VERSION 5.7 ;
  NOWIREEXTENSIONATPIN ON ;
  DIVIDERCHAR "/" ;
  BUSBITCHARS "[]" ;
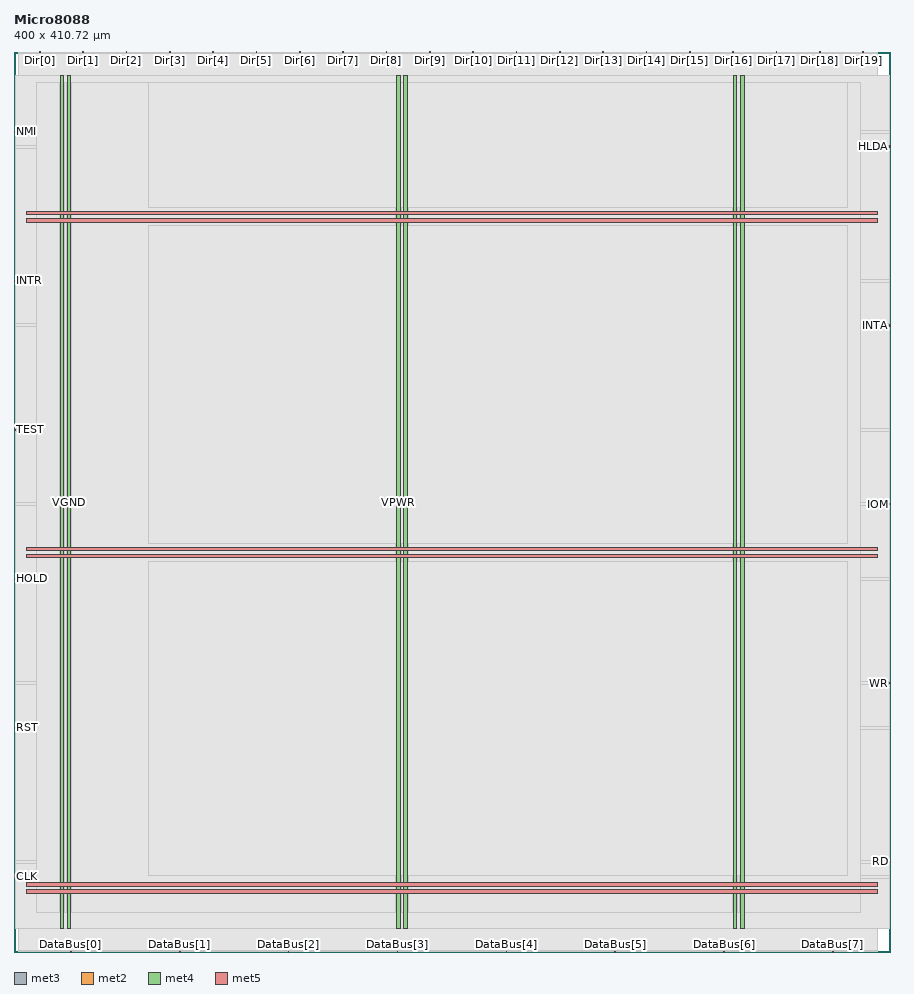
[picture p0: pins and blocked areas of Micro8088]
MACRO Micro8088
  CLASS BLOCK ;
  FOREIGN Micro8088 ;
  ORIGIN 0.000 0.000 ;
  SIZE 400.000 BY 410.720 ;
  PIN CLK
    DIRECTION INPUT ;
    USE SIGNAL ;
    ANTENNAGATEAREA 0.852000 ;
    PORT
      LAYER met3 ;
        RECT 0.000 34.040 0.600 34.640 ;
    END
  END CLK
  PIN DataBus[0]
    DIRECTION INOUT ;
    USE SIGNAL ;
    ANTENNAGATEAREA 0.252000 ;
    ANTENNADIFFAREA 0.445500 ;
    PORT
      LAYER met2 ;
        RECT 25.850 0.000 26.130 0.280 ;
    END
  END DataBus[0]
  PIN DataBus[1]
    DIRECTION INOUT ;
    USE SIGNAL ;
    ANTENNAGATEAREA 0.252000 ;
    ANTENNADIFFAREA 0.445500 ;
    PORT
      LAYER met2 ;
        RECT 75.530 0.000 75.810 0.280 ;
    END
  END DataBus[1]
  PIN DataBus[2]
    DIRECTION INOUT ;
    USE SIGNAL ;
    ANTENNAGATEAREA 0.252000 ;
    ANTENNADIFFAREA 0.445500 ;
    PORT
      LAYER met2 ;
        RECT 125.210 0.000 125.490 0.280 ;
    END
  END DataBus[2]
  PIN DataBus[3]
    DIRECTION INOUT ;
    USE SIGNAL ;
    ANTENNAGATEAREA 0.252000 ;
    ANTENNADIFFAREA 0.445500 ;
    PORT
      LAYER met2 ;
        RECT 174.890 0.000 175.170 0.280 ;
    END
  END DataBus[3]
  PIN DataBus[4]
    DIRECTION INOUT ;
    USE SIGNAL ;
    ANTENNAGATEAREA 0.252000 ;
    ANTENNADIFFAREA 0.445500 ;
    PORT
      LAYER met2 ;
        RECT 224.570 0.000 224.850 0.280 ;
    END
  END DataBus[4]
  PIN DataBus[5]
    DIRECTION INOUT ;
    USE SIGNAL ;
    ANTENNAGATEAREA 0.252000 ;
    ANTENNADIFFAREA 0.445500 ;
    PORT
      LAYER met2 ;
        RECT 274.250 0.000 274.530 0.280 ;
    END
  END DataBus[5]
  PIN DataBus[6]
    DIRECTION INOUT ;
    USE SIGNAL ;
    ANTENNAGATEAREA 0.252000 ;
    ANTENNADIFFAREA 0.445500 ;
    PORT
      LAYER met2 ;
        RECT 323.930 0.000 324.210 0.280 ;
    END
  END DataBus[6]
  PIN DataBus[7]
    DIRECTION INOUT ;
    USE SIGNAL ;
    ANTENNAGATEAREA 0.252000 ;
    ANTENNADIFFAREA 0.445500 ;
    PORT
      LAYER met2 ;
        RECT 373.610 0.000 373.890 0.280 ;
    END
  END DataBus[7]
  PIN Dir[0]
    DIRECTION OUTPUT ;
    USE SIGNAL ;
    ANTENNADIFFAREA 0.702900 ;
    PORT
      LAYER met2 ;
        RECT 11.590 410.440 11.870 410.720 ;
    END
  END Dir[0]
  PIN Dir[10]
    DIRECTION OUTPUT ;
    USE SIGNAL ;
    ANTENNADIFFAREA 0.702900 ;
    PORT
      LAYER met2 ;
        RECT 209.390 410.440 209.670 410.720 ;
    END
  END Dir[10]
  PIN Dir[11]
    DIRECTION OUTPUT ;
    USE SIGNAL ;
    ANTENNADIFFAREA 0.702900 ;
    PORT
      LAYER met2 ;
        RECT 229.170 410.440 229.450 410.720 ;
    END
  END Dir[11]
  PIN Dir[12]
    DIRECTION OUTPUT ;
    USE SIGNAL ;
    ANTENNADIFFAREA 0.702900 ;
    PORT
      LAYER met2 ;
        RECT 248.950 410.440 249.230 410.720 ;
    END
  END Dir[12]
  PIN Dir[13]
    DIRECTION OUTPUT ;
    USE SIGNAL ;
    ANTENNADIFFAREA 0.702900 ;
    PORT
      LAYER met2 ;
        RECT 268.730 410.440 269.010 410.720 ;
    END
  END Dir[13]
  PIN Dir[14]
    DIRECTION OUTPUT ;
    USE SIGNAL ;
    ANTENNADIFFAREA 0.702900 ;
    PORT
      LAYER met2 ;
        RECT 288.510 410.440 288.790 410.720 ;
    END
  END Dir[14]
  PIN Dir[15]
    DIRECTION OUTPUT ;
    USE SIGNAL ;
    ANTENNADIFFAREA 0.702900 ;
    PORT
      LAYER met2 ;
        RECT 308.290 410.440 308.570 410.720 ;
    END
  END Dir[15]
  PIN Dir[16]
    DIRECTION OUTPUT ;
    USE SIGNAL ;
    ANTENNADIFFAREA 0.702900 ;
    PORT
      LAYER met2 ;
        RECT 328.070 410.440 328.350 410.720 ;
    END
  END Dir[16]
  PIN Dir[17]
    DIRECTION OUTPUT ;
    USE SIGNAL ;
    ANTENNADIFFAREA 0.702900 ;
    PORT
      LAYER met2 ;
        RECT 347.850 410.440 348.130 410.720 ;
    END
  END Dir[17]
  PIN Dir[18]
    DIRECTION OUTPUT ;
    USE SIGNAL ;
    ANTENNADIFFAREA 0.702900 ;
    PORT
      LAYER met2 ;
        RECT 367.630 410.440 367.910 410.720 ;
    END
  END Dir[18]
  PIN Dir[19]
    DIRECTION OUTPUT ;
    USE SIGNAL ;
    ANTENNADIFFAREA 0.702900 ;
    PORT
      LAYER met2 ;
        RECT 387.410 410.440 387.690 410.720 ;
    END
  END Dir[19]
  PIN Dir[1]
    DIRECTION OUTPUT ;
    USE SIGNAL ;
    ANTENNADIFFAREA 0.702900 ;
    PORT
      LAYER met2 ;
        RECT 31.370 410.440 31.650 410.720 ;
    END
  END Dir[1]
  PIN Dir[2]
    DIRECTION OUTPUT ;
    USE SIGNAL ;
    ANTENNADIFFAREA 0.702900 ;
    PORT
      LAYER met2 ;
        RECT 51.150 410.440 51.430 410.720 ;
    END
  END Dir[2]
  PIN Dir[3]
    DIRECTION OUTPUT ;
    USE SIGNAL ;
    ANTENNADIFFAREA 0.702900 ;
    PORT
      LAYER met2 ;
        RECT 70.930 410.440 71.210 410.720 ;
    END
  END Dir[3]
  PIN Dir[4]
    DIRECTION OUTPUT ;
    USE SIGNAL ;
    ANTENNADIFFAREA 0.702900 ;
    PORT
      LAYER met2 ;
        RECT 90.710 410.440 90.990 410.720 ;
    END
  END Dir[4]
  PIN Dir[5]
    DIRECTION OUTPUT ;
    USE SIGNAL ;
    ANTENNADIFFAREA 0.702900 ;
    PORT
      LAYER met2 ;
        RECT 110.490 410.440 110.770 410.720 ;
    END
  END Dir[5]
  PIN Dir[6]
    DIRECTION OUTPUT ;
    USE SIGNAL ;
    ANTENNADIFFAREA 0.702900 ;
    PORT
      LAYER met2 ;
        RECT 130.270 410.440 130.550 410.720 ;
    END
  END Dir[6]
  PIN Dir[7]
    DIRECTION OUTPUT ;
    USE SIGNAL ;
    ANTENNADIFFAREA 0.702900 ;
    PORT
      LAYER met2 ;
        RECT 150.050 410.440 150.330 410.720 ;
    END
  END Dir[7]
  PIN Dir[8]
    DIRECTION OUTPUT ;
    USE SIGNAL ;
    ANTENNADIFFAREA 0.702900 ;
    PORT
      LAYER met2 ;
        RECT 169.830 410.440 170.110 410.720 ;
    END
  END Dir[8]
  PIN Dir[9]
    DIRECTION OUTPUT ;
    USE SIGNAL ;
    ANTENNADIFFAREA 0.702900 ;
    PORT
      LAYER met2 ;
        RECT 189.610 410.440 189.890 410.720 ;
    END
  END Dir[9]
  PIN HLDA
    DIRECTION OUTPUT ;
    USE SIGNAL ;
    ANTENNADIFFAREA 0.702900 ;
    PORT
      LAYER met3 ;
        RECT 399.400 367.240 400.000 367.840 ;
    END
  END HLDA
  PIN HOLD
    DIRECTION INPUT ;
    USE SIGNAL ;
    ANTENNAGATEAREA 0.126000 ;
    PORT
      LAYER met3 ;
        RECT 0.000 170.040 0.600 170.640 ;
    END
  END HOLD
  PIN INTA
    DIRECTION OUTPUT ;
    USE SIGNAL ;
    ANTENNADIFFAREA 0.702900 ;
    PORT
      LAYER met3 ;
        RECT 399.400 285.640 400.000 286.240 ;
    END
  END INTA
  PIN INTR
    DIRECTION INPUT ;
    USE SIGNAL ;
    ANTENNAGATEAREA 0.126000 ;
    PORT
      LAYER met3 ;
        RECT 0.000 306.040 0.600 306.640 ;
    END
  END INTR
  PIN IOM
    DIRECTION OUTPUT ;
    USE SIGNAL ;
    ANTENNADIFFAREA 0.702900 ;
    PORT
      LAYER met3 ;
        RECT 399.400 204.040 400.000 204.640 ;
    END
  END IOM
  PIN NMI
    DIRECTION INPUT ;
    USE SIGNAL ;
    ANTENNAGATEAREA 0.213000 ;
    PORT
      LAYER met3 ;
        RECT 0.000 374.040 0.600 374.640 ;
    END
  END NMI
  PIN RD
    DIRECTION OUTPUT ;
    USE SIGNAL ;
    ANTENNADIFFAREA 0.702900 ;
    PORT
      LAYER met3 ;
        RECT 399.400 40.840 400.000 41.440 ;
    END
  END RD
  PIN RST
    DIRECTION INPUT ;
    USE SIGNAL ;
    ANTENNAGATEAREA 0.126000 ;
    PORT
      LAYER met3 ;
        RECT 0.000 102.040 0.600 102.640 ;
    END
  END RST
  PIN TEST
    DIRECTION INPUT ;
    USE SIGNAL ;
    ANTENNAGATEAREA 0.126000 ;
    PORT
      LAYER met3 ;
        RECT 0.000 238.040 0.600 238.640 ;
    END
  END TEST
  PIN VGND
    DIRECTION INOUT ;
    USE GROUND ;
    PORT
      LAYER met4 ;
        RECT 24.340 10.640 25.940 400.080 ;
    END
    PORT
      LAYER met4 ;
        RECT 177.940 10.640 179.540 400.080 ;
    END
    PORT
      LAYER met4 ;
        RECT 331.540 10.640 333.140 400.080 ;
    END
    PORT
      LAYER met5 ;
        RECT 5.520 30.030 394.220 31.630 ;
    END
    PORT
      LAYER met5 ;
        RECT 5.520 183.210 394.220 184.810 ;
    END
    PORT
      LAYER met5 ;
        RECT 5.520 336.390 394.220 337.990 ;
    END
  END VGND
  PIN VPWR
    DIRECTION INOUT ;
    USE POWER ;
    PORT
      LAYER met4 ;
        RECT 21.040 10.640 22.640 400.080 ;
    END
    PORT
      LAYER met4 ;
        RECT 174.640 10.640 176.240 400.080 ;
    END
    PORT
      LAYER met4 ;
        RECT 328.240 10.640 329.840 400.080 ;
    END
    PORT
      LAYER met5 ;
        RECT 5.520 26.730 394.220 28.330 ;
    END
    PORT
      LAYER met5 ;
        RECT 5.520 179.910 394.220 181.510 ;
    END
    PORT
      LAYER met5 ;
        RECT 5.520 333.090 394.220 334.690 ;
    END
  END VPWR
  PIN WR
    DIRECTION OUTPUT ;
    USE SIGNAL ;
    ANTENNADIFFAREA 0.702900 ;
    PORT
      LAYER met3 ;
        RECT 399.400 122.440 400.000 123.040 ;
    END
  END WR
  OBS
      LAYER nwell ;
        RECT 5.330 10.795 394.410 400.030 ;
      LAYER li1 ;
        RECT 5.520 10.795 394.220 399.925 ;
      LAYER met1 ;
        RECT 1.910 0.040 394.220 400.080 ;
      LAYER met2 ;
        RECT 1.930 410.160 11.310 410.440 ;
        RECT 12.150 410.160 31.090 410.440 ;
        RECT 31.930 410.160 50.870 410.440 ;
        RECT 51.710 410.160 70.650 410.440 ;
        RECT 71.490 410.160 90.430 410.440 ;
        RECT 91.270 410.160 110.210 410.440 ;
        RECT 111.050 410.160 129.990 410.440 ;
        RECT 130.830 410.160 149.770 410.440 ;
        RECT 150.610 410.160 169.550 410.440 ;
        RECT 170.390 410.160 189.330 410.440 ;
        RECT 190.170 410.160 209.110 410.440 ;
        RECT 209.950 410.160 228.890 410.440 ;
        RECT 229.730 410.160 248.670 410.440 ;
        RECT 249.510 410.160 268.450 410.440 ;
        RECT 269.290 410.160 288.230 410.440 ;
        RECT 289.070 410.160 308.010 410.440 ;
        RECT 308.850 410.160 327.790 410.440 ;
        RECT 328.630 410.160 347.570 410.440 ;
        RECT 348.410 410.160 367.350 410.440 ;
        RECT 368.190 410.160 387.130 410.440 ;
        RECT 387.970 410.160 394.120 410.440 ;
        RECT 1.930 0.560 394.120 410.160 ;
        RECT 1.930 0.010 25.570 0.560 ;
        RECT 26.410 0.010 75.250 0.560 ;
        RECT 76.090 0.010 124.930 0.560 ;
        RECT 125.770 0.010 174.610 0.560 ;
        RECT 175.450 0.010 224.290 0.560 ;
        RECT 225.130 0.010 273.970 0.560 ;
        RECT 274.810 0.010 323.650 0.560 ;
        RECT 324.490 0.010 373.330 0.560 ;
        RECT 374.170 0.010 394.120 0.560 ;
      LAYER met3 ;
        RECT 0.600 375.040 399.400 400.005 ;
        RECT 1.000 373.640 399.400 375.040 ;
        RECT 0.600 368.240 399.400 373.640 ;
        RECT 0.600 366.840 399.000 368.240 ;
        RECT 0.600 307.040 399.400 366.840 ;
        RECT 1.000 305.640 399.400 307.040 ;
        RECT 0.600 286.640 399.400 305.640 ;
        RECT 0.600 285.240 399.000 286.640 ;
        RECT 0.600 239.040 399.400 285.240 ;
        RECT 1.000 237.640 399.400 239.040 ;
        RECT 0.600 205.040 399.400 237.640 ;
        RECT 0.600 203.640 399.000 205.040 ;
        RECT 0.600 171.040 399.400 203.640 ;
        RECT 1.000 169.640 399.400 171.040 ;
        RECT 0.600 123.440 399.400 169.640 ;
        RECT 0.600 122.040 399.000 123.440 ;
        RECT 0.600 103.040 399.400 122.040 ;
        RECT 1.000 101.640 399.400 103.040 ;
        RECT 0.600 41.840 399.400 101.640 ;
        RECT 0.600 40.440 399.000 41.840 ;
        RECT 0.600 35.040 399.400 40.440 ;
        RECT 1.000 33.640 399.400 35.040 ;
        RECT 0.600 10.715 399.400 33.640 ;
      LAYER met4 ;
        RECT 10.415 17.855 20.640 396.690 ;
        RECT 23.040 17.855 23.940 396.690 ;
        RECT 26.340 17.855 174.240 396.690 ;
        RECT 176.640 17.855 177.540 396.690 ;
        RECT 179.940 17.855 327.840 396.690 ;
        RECT 330.240 17.855 331.140 396.690 ;
        RECT 333.540 17.855 386.105 396.690 ;
      LAYER met5 ;
        RECT 61.300 339.590 380.300 396.900 ;
        RECT 61.300 186.410 380.300 331.490 ;
        RECT 61.300 34.900 380.300 178.310 ;
  END
END Micro8088
END LIBRARY

